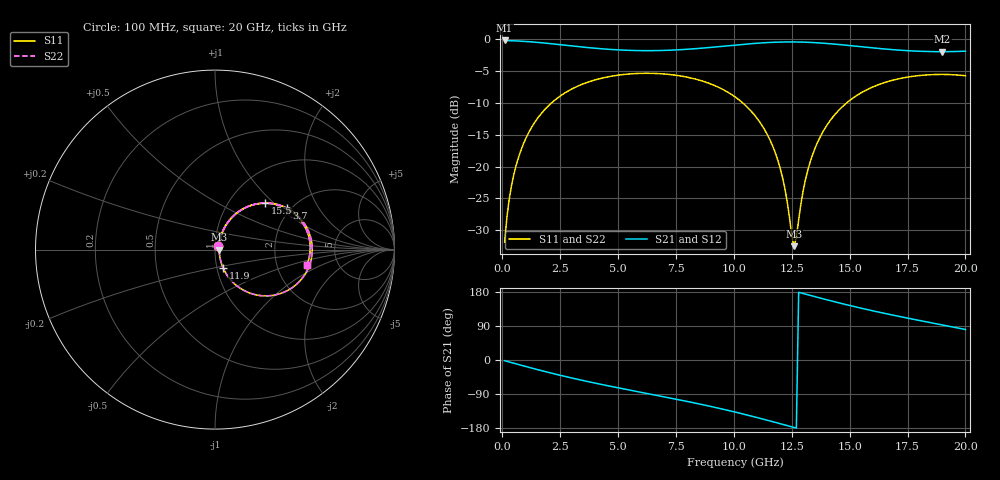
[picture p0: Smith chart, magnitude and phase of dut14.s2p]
! Touchstone file exported from HFSS 2026.1.0
!  File:  C:/ffzhzh/LocalFiles/Ansys_Project_Files/temp_test_TSV_RDL_14_1782980230_45748.aedt
!  Generated:  04:31:00 PM Jul  2, 2026
!  Design:  TSV_RDL
!  Project:  temp_test_TSV_RDL_14_1782980230_45748
! Variables:
!  h_bsmrdl = 4.87um
!  h_ox = 20um
!  h_rdl = 5um
!  h_sub = 59.69um
!  h_tmrdl = 3.82um
!  h_tsv = 59.69um
!  h_via = 3um
!  l_bsmrdl = 299.95um
!  l_sub = 5011.17um
!  l_tmrdl = 895.4um
!  m_sub = 200um
!  pitch = 53.04um
!  r_tsv = 10.23um
!  s_tmrdl = 10um
!  w_bsmrdl = 18.19um
!  w_sub = 500um
!  w_tmrdl = 25.05um
!  x_tsv_center1 = 907.925um
!  x_tsv_center2 = 1226.065um
!  x_tsv_center3 = 2146.515um
!  x_tsv_center4 = 2464.655um
!  x_tsv_center5 = 3385.105um
!  x_tsv_center6 = 3703.245um
# GHz S MA R 50.000000
! Terminal data exported
! Port[1] = TM_RDL1_1_T1
! Port[2] = TM_RDL5_1_T1
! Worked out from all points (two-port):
!   200 points, 100 MHz to 20 GHz, reference 50 ohm
!   highest |S21| = -0.16 dB at 100 MHz (marker M1); lowest = -1.9 dB at 19 GHz (marker M2)
!   |S21| within 3 dB of the highest: start of sweep to end of sweep
!   lowest |S11| = -32.5 dB at 12.6 GHz (marker M3), VSWR 1.05, Z = 52.4 - j0.108 ohm
!   |S11| at or under -10 dB: start of sweep to 2.121 GHz; 10.39 GHz to 14.87 GHz (4.477 GHz wide, 35.5 % of centre)
!   |S22| runs from -32.5 to -5.3 dB; largest |S21 - S12| = 1.6e-14
!   S11 on the Smith chart (normalised r, x): 100 MHz: 1.04, +0.04; 3.7 GHz: 1.90, +1.12; 11.9 GHz: 1.07, -0.22; 15.5 GHz: 1.46, +0.88; 20 GHz: 2.96, -0.71
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0.1  0.02545 43.3  0.9819 -1.8  0.9819 -1.8  0.02545 43.3
! Gamma 0 0 0 0
! Port Impedance 50 0 50 0
0.3  0.05554 63.9  0.9789 -5.2  0.9789 -5.2  0.05554 63.9
0.5  0.08687 67.5  0.9756 -8.6  0.9756 -8.6  0.08687 67.5
1.1  0.179 64.3  0.9617 -18.6  0.9617 -18.6  0.179 64.3
2.1  0.3138 51.4  0.9262 -34.4  0.9262 -34.4  0.3138 51.4
3.5  0.4478 32.7  0.87 -54.3  0.87 -54.3  0.4478 32.7
3.7  0.4617 30.2  0.8629 -57.0  0.8629 -57.0  0.4617 30.2
5.3  0.5314 10.9  0.8229 -77.0  0.8229 -77.0  0.5314 10.9
6.8  0.5381 -6.3  0.8181 -94.8  0.8181 -94.8  0.5381 -6.3
8.6  0.4733 -27.6  0.8533 -117.2  0.8533 -117.2  0.4733 -27.6
10.1  0.3485 -46.8  0.9044 -138.0  0.9044 -138.0  0.3485 -46.8
11.2  0.2131 -60.8  0.9392 -155.0  0.9392 -155.0  0.2131 -60.8
11.9  0.1121 -66.1  0.9526 -166.4  0.9526 -166.4  0.1122 -66.1
12.2  0.0678 -62.7  0.9554 -171.3  0.9554 -171.3  0.06783 -62.7
12.6  0.02368 -2.5  0.9558 -178.0  0.9558 -178.0  0.02377 -2.5
13  0.06542 62.7  0.9526 175.4  0.9526 175.4  0.06546 62.6
13.4  0.124 66.5  0.9459 168.8  0.9459 168.8  0.124 66.4
14.2  0.2355 59.3  0.9241 156.0  0.9241 156.0  0.2355 59.2
15.5  0.3807 42.8  0.8764 136.7  0.8764 136.7  0.3807 42.7
16.7  0.4691 27.9  0.8356 120.6  0.8356 120.6  0.4691 27.8
19  0.5308 1.5  0.8013 92.5  0.8013 92.5  0.5308 1.4
20  0.5182 -9.7  0.8085 80.5  0.8085 80.5  0.5182 -9.8
